VERSION 5.7 ;
  NOWIREEXTENSIONATPIN ON ;
  DIVIDERCHAR "/" ;
  BUSBITCHARS "[]" ;
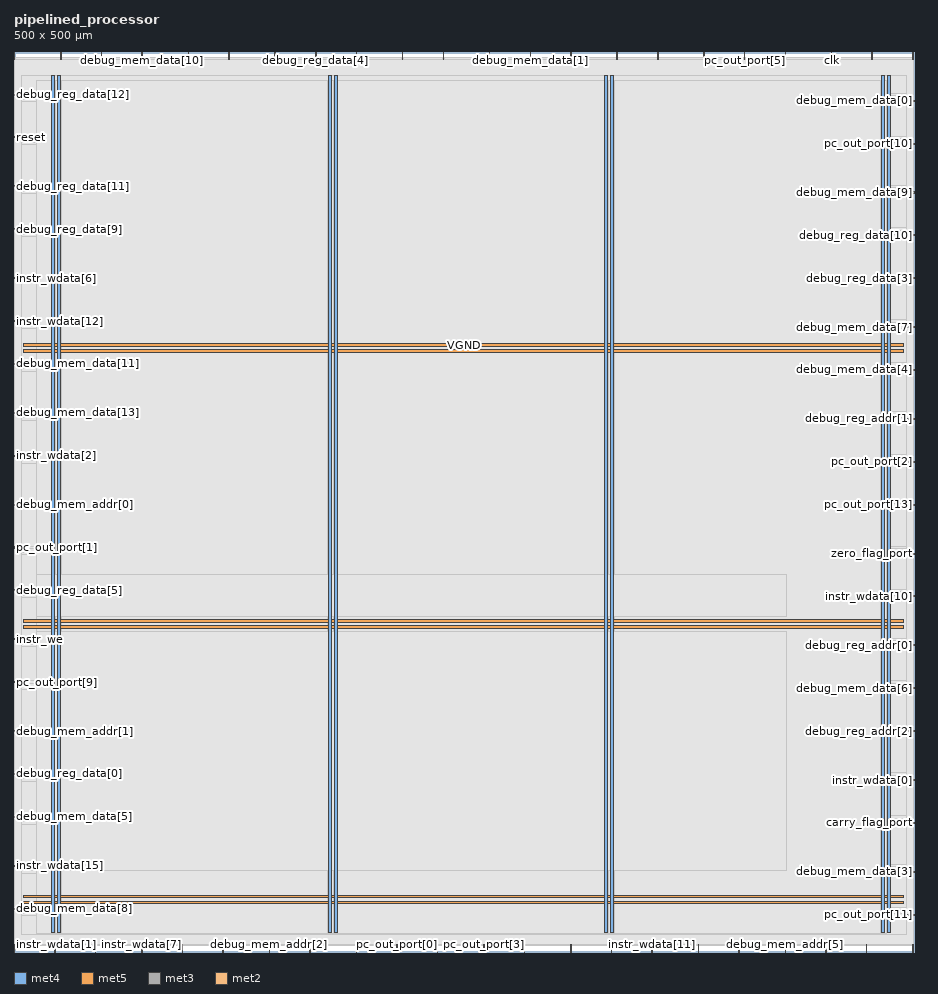
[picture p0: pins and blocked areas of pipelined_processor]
MACRO pipelined_processor
  CLASS BLOCK ;
  FOREIGN pipelined_processor ;
  ORIGIN 0.000 0.000 ;
  SIZE 500.000 BY 500.000 ;
  PIN VGND
    DIRECTION INOUT ;
    USE GROUND ;
    PORT
      LAYER met4 ;
        RECT 24.340 10.640 25.940 487.120 ;
    END
    PORT
      LAYER met4 ;
        RECT 177.940 10.640 179.540 487.120 ;
    END
    PORT
      LAYER met4 ;
        RECT 331.540 10.640 333.140 487.120 ;
    END
    PORT
      LAYER met4 ;
        RECT 485.140 10.640 486.740 487.120 ;
    END
    PORT
      LAYER met5 ;
        RECT 5.280 30.030 494.280 31.630 ;
    END
    PORT
      LAYER met5 ;
        RECT 5.280 183.210 494.280 184.810 ;
    END
    PORT
      LAYER met5 ;
        RECT 5.280 336.390 494.280 337.990 ;
    END
  END VGND
  PIN VPWR
    DIRECTION INOUT ;
    USE POWER ;
    PORT
      LAYER met4 ;
        RECT 21.040 10.640 22.640 487.120 ;
    END
    PORT
      LAYER met4 ;
        RECT 174.640 10.640 176.240 487.120 ;
    END
    PORT
      LAYER met4 ;
        RECT 328.240 10.640 329.840 487.120 ;
    END
    PORT
      LAYER met4 ;
        RECT 481.840 10.640 483.440 487.120 ;
    END
    PORT
      LAYER met5 ;
        RECT 5.280 26.730 494.280 28.330 ;
    END
    PORT
      LAYER met5 ;
        RECT 5.280 179.910 494.280 181.510 ;
    END
    PORT
      LAYER met5 ;
        RECT 5.280 333.090 494.280 334.690 ;
    END
  END VPWR
  PIN carry_flag_port
    DIRECTION OUTPUT TRISTATE ;
    USE SIGNAL ;
    ANTENNADIFFAREA 0.445500 ;
    PORT
      LAYER met3 ;
        RECT 496.000 71.440 500.000 72.040 ;
    END
  END carry_flag_port
  PIN clk
    DIRECTION INPUT ;
    USE SIGNAL ;
    ANTENNAGATEAREA 1.286700 ;
    ANTENNADIFFAREA 0.434700 ;
    PORT
      LAYER met2 ;
        RECT 454.110 496.000 454.390 500.000 ;
    END
  END clk
  PIN debug_mem_addr[0]
    DIRECTION INPUT ;
    USE SIGNAL ;
    ANTENNAGATEAREA 0.213000 ;
    PORT
      LAYER met3 ;
        RECT 0.000 248.240 4.000 248.840 ;
    END
  END debug_mem_addr[0]
  PIN debug_mem_addr[1]
    DIRECTION INPUT ;
    USE SIGNAL ;
    ANTENNAGATEAREA 0.213000 ;
    PORT
      LAYER met3 ;
        RECT 0.000 122.440 4.000 123.040 ;
    END
  END debug_mem_addr[1]
  PIN debug_mem_addr[2]
    DIRECTION INPUT ;
    USE SIGNAL ;
    ANTENNAGATEAREA 0.159000 ;
    PORT
      LAYER met2 ;
        RECT 141.770 0.000 142.050 4.000 ;
    END
  END debug_mem_addr[2]
  PIN debug_mem_addr[3]
    DIRECTION INPUT ;
    USE SIGNAL ;
    ANTENNAGATEAREA 0.213000 ;
    PORT
      LAYER met2 ;
        RECT 235.150 0.000 235.430 4.000 ;
    END
  END debug_mem_addr[3]
  PIN debug_mem_addr[4]
    DIRECTION INPUT ;
    USE SIGNAL ;
    ANTENNAGATEAREA 0.247500 ;
    PORT
      LAYER met2 ;
        RECT 402.590 0.000 402.870 4.000 ;
    END
  END debug_mem_addr[4]
  PIN debug_mem_addr[5]
    DIRECTION INPUT ;
    USE SIGNAL ;
    ANTENNAGATEAREA 0.247500 ;
    PORT
      LAYER met2 ;
        RECT 428.350 0.000 428.630 4.000 ;
    END
  END debug_mem_addr[5]
  PIN debug_mem_data[0]
    DIRECTION OUTPUT TRISTATE ;
    USE SIGNAL ;
    ANTENNADIFFAREA 0.445500 ;
    PORT
      LAYER met3 ;
        RECT 496.000 472.640 500.000 473.240 ;
    END
  END debug_mem_data[0]
  PIN debug_mem_data[10]
    DIRECTION OUTPUT TRISTATE ;
    USE SIGNAL ;
    ANTENNADIFFAREA 0.795200 ;
    PORT
      LAYER met2 ;
        RECT 70.930 496.000 71.210 500.000 ;
    END
  END debug_mem_data[10]
  PIN debug_mem_data[11]
    DIRECTION OUTPUT TRISTATE ;
    USE SIGNAL ;
    ANTENNADIFFAREA 0.795200 ;
    PORT
      LAYER met3 ;
        RECT 0.000 326.440 4.000 327.040 ;
    END
  END debug_mem_data[11]
  PIN debug_mem_data[12]
    DIRECTION OUTPUT TRISTATE ;
    USE SIGNAL ;
    ANTENNADIFFAREA 0.795200 ;
    PORT
      LAYER met2 ;
        RECT 264.130 496.000 264.410 500.000 ;
    END
  END debug_mem_data[12]
  PIN debug_mem_data[13]
    DIRECTION OUTPUT TRISTATE ;
    USE SIGNAL ;
    ANTENNADIFFAREA 0.795200 ;
    PORT
      LAYER met3 ;
        RECT 0.000 299.240 4.000 299.840 ;
    END
  END debug_mem_data[13]
  PIN debug_mem_data[14]
    DIRECTION OUTPUT TRISTATE ;
    USE SIGNAL ;
    ANTENNADIFFAREA 0.795200 ;
    PORT
      LAYER met2 ;
        RECT 499.190 0.000 499.470 4.000 ;
    END
  END debug_mem_data[14]
  PIN debug_mem_data[15]
    DIRECTION OUTPUT TRISTATE ;
    USE SIGNAL ;
    ANTENNADIFFAREA 0.795200 ;
    PORT
      LAYER met2 ;
        RECT 473.430 0.000 473.710 4.000 ;
    END
  END debug_mem_data[15]
  PIN debug_mem_data[1]
    DIRECTION OUTPUT TRISTATE ;
    USE SIGNAL ;
    ANTENNADIFFAREA 0.795200 ;
    PORT
      LAYER met2 ;
        RECT 286.670 496.000 286.950 500.000 ;
    END
  END debug_mem_data[1]
  PIN debug_mem_data[2]
    DIRECTION OUTPUT TRISTATE ;
    USE SIGNAL ;
    ANTENNADIFFAREA 0.795200 ;
    PORT
      LAYER met2 ;
        RECT 383.270 496.000 383.550 500.000 ;
    END
  END debug_mem_data[2]
  PIN debug_mem_data[3]
    DIRECTION OUTPUT TRISTATE ;
    USE SIGNAL ;
    ANTENNADIFFAREA 0.445500 ;
    PORT
      LAYER met3 ;
        RECT 496.000 44.240 500.000 44.840 ;
    END
  END debug_mem_data[3]
  PIN debug_mem_data[4]
    DIRECTION OUTPUT TRISTATE ;
    USE SIGNAL ;
    ANTENNADIFFAREA 0.795200 ;
    PORT
      LAYER met3 ;
        RECT 496.000 323.040 500.000 323.640 ;
    END
  END debug_mem_data[4]
  PIN debug_mem_data[5]
    DIRECTION OUTPUT TRISTATE ;
    USE SIGNAL ;
    ANTENNADIFFAREA 0.795200 ;
    PORT
      LAYER met3 ;
        RECT 0.000 74.840 4.000 75.440 ;
    END
  END debug_mem_data[5]
  PIN debug_mem_data[6]
    DIRECTION OUTPUT TRISTATE ;
    USE SIGNAL ;
    ANTENNADIFFAREA 0.795200 ;
    PORT
      LAYER met3 ;
        RECT 496.000 146.240 500.000 146.840 ;
    END
  END debug_mem_data[6]
  PIN debug_mem_data[7]
    DIRECTION OUTPUT TRISTATE ;
    USE SIGNAL ;
    ANTENNADIFFAREA 0.445500 ;
    PORT
      LAYER met3 ;
        RECT 496.000 346.840 500.000 347.440 ;
    END
  END debug_mem_data[7]
  PIN debug_mem_data[8]
    DIRECTION OUTPUT TRISTATE ;
    USE SIGNAL ;
    ANTENNADIFFAREA 0.795200 ;
    PORT
      LAYER met3 ;
        RECT 0.000 23.840 4.000 24.440 ;
    END
  END debug_mem_data[8]
  PIN debug_mem_data[9]
    DIRECTION OUTPUT TRISTATE ;
    USE SIGNAL ;
    ANTENNADIFFAREA 0.445500 ;
    PORT
      LAYER met3 ;
        RECT 496.000 421.640 500.000 422.240 ;
    END
  END debug_mem_data[9]
  PIN debug_reg_addr[0]
    DIRECTION INPUT ;
    USE SIGNAL ;
    ANTENNAGATEAREA 0.247500 ;
    PORT
      LAYER met3 ;
        RECT 496.000 170.040 500.000 170.640 ;
    END
  END debug_reg_addr[0]
  PIN debug_reg_addr[1]
    DIRECTION INPUT ;
    USE SIGNAL ;
    ANTENNAGATEAREA 0.247500 ;
    PORT
      LAYER met3 ;
        RECT 496.000 295.840 500.000 296.440 ;
    END
  END debug_reg_addr[1]
  PIN debug_reg_addr[2]
    DIRECTION INPUT ;
    USE SIGNAL ;
    ANTENNAGATEAREA 0.495000 ;
    PORT
      LAYER met3 ;
        RECT 496.000 122.440 500.000 123.040 ;
    END
  END debug_reg_addr[2]
  PIN debug_reg_data[0]
    DIRECTION OUTPUT TRISTATE ;
    USE SIGNAL ;
    ANTENNADIFFAREA 0.795200 ;
    PORT
      LAYER met3 ;
        RECT 0.000 98.640 4.000 99.240 ;
    END
  END debug_reg_data[0]
  PIN debug_reg_data[10]
    DIRECTION OUTPUT TRISTATE ;
    USE SIGNAL ;
    ANTENNADIFFAREA 0.445500 ;
    PORT
      LAYER met3 ;
        RECT 496.000 397.840 500.000 398.440 ;
    END
  END debug_reg_data[10]
  PIN debug_reg_data[11]
    DIRECTION OUTPUT TRISTATE ;
    USE SIGNAL ;
    ANTENNADIFFAREA 0.795200 ;
    PORT
      LAYER met3 ;
        RECT 0.000 425.040 4.000 425.640 ;
    END
  END debug_reg_data[11]
  PIN debug_reg_data[12]
    DIRECTION OUTPUT TRISTATE ;
    USE SIGNAL ;
    ANTENNADIFFAREA 0.795200 ;
    PORT
      LAYER met3 ;
        RECT 0.000 476.040 4.000 476.640 ;
    END
  END debug_reg_data[12]
  PIN debug_reg_data[13]
    DIRECTION OUTPUT TRISTATE ;
    USE SIGNAL ;
    ANTENNADIFFAREA 0.795200 ;
    PORT
      LAYER met2 ;
        RECT 0.090 496.000 0.370 500.000 ;
    END
  END debug_reg_data[13]
  PIN debug_reg_data[14]
    DIRECTION OUTPUT TRISTATE ;
    USE SIGNAL ;
    ANTENNADIFFAREA 0.795200 ;
    PORT
      LAYER met2 ;
        RECT 45.170 0.000 45.450 4.000 ;
    END
  END debug_reg_data[14]
  PIN debug_reg_data[15]
    DIRECTION OUTPUT TRISTATE ;
    USE SIGNAL ;
    ANTENNADIFFAREA 0.795200 ;
    PORT
      LAYER met2 ;
        RECT 309.210 496.000 309.490 500.000 ;
    END
  END debug_reg_data[15]
  PIN debug_reg_data[1]
    DIRECTION OUTPUT TRISTATE ;
    USE SIGNAL ;
    ANTENNADIFFAREA 0.795200 ;
    PORT
      LAYER met2 ;
        RECT 190.070 0.000 190.350 4.000 ;
    END
  END debug_reg_data[1]
  PIN debug_reg_data[2]
    DIRECTION OUTPUT TRISTATE ;
    USE SIGNAL ;
    ANTENNADIFFAREA 0.795200 ;
    PORT
      LAYER met2 ;
        RECT 309.210 0.000 309.490 4.000 ;
    END
  END debug_reg_data[2]
  PIN debug_reg_data[3]
    DIRECTION OUTPUT TRISTATE ;
    USE SIGNAL ;
    ANTENNADIFFAREA 0.445500 ;
    PORT
      LAYER met3 ;
        RECT 496.000 374.040 500.000 374.640 ;
    END
  END debug_reg_data[3]
  PIN debug_reg_data[4]
    DIRECTION OUTPUT TRISTATE ;
    USE SIGNAL ;
    ANTENNADIFFAREA 0.795200 ;
    PORT
      LAYER met2 ;
        RECT 167.530 496.000 167.810 500.000 ;
    END
  END debug_reg_data[4]
  PIN debug_reg_data[5]
    DIRECTION OUTPUT TRISTATE ;
    USE SIGNAL ;
    ANTENNADIFFAREA 0.795200 ;
    PORT
      LAYER met3 ;
        RECT 0.000 200.640 4.000 201.240 ;
    END
  END debug_reg_data[5]
  PIN debug_reg_data[6]
    DIRECTION OUTPUT TRISTATE ;
    USE SIGNAL ;
    ANTENNADIFFAREA 0.795200 ;
    PORT
      LAYER met2 ;
        RECT 116.010 0.000 116.290 4.000 ;
    END
  END debug_reg_data[6]
  PIN debug_reg_data[7]
    DIRECTION OUTPUT TRISTATE ;
    USE SIGNAL ;
    ANTENNADIFFAREA 0.795200 ;
    PORT
      LAYER met2 ;
        RECT 380.050 0.000 380.330 4.000 ;
    END
  END debug_reg_data[7]
  PIN debug_reg_data[8]
    DIRECTION OUTPUT TRISTATE ;
    USE SIGNAL ;
    ANTENNADIFFAREA 0.795200 ;
    PORT
      LAYER met2 ;
        RECT 357.510 496.000 357.790 500.000 ;
    END
  END debug_reg_data[8]
  PIN debug_reg_data[9]
    DIRECTION OUTPUT TRISTATE ;
    USE SIGNAL ;
    ANTENNADIFFAREA 0.795200 ;
    PORT
      LAYER met3 ;
        RECT 0.000 401.240 4.000 401.840 ;
    END
  END debug_reg_data[9]
  PIN instr_waddr[0]
    DIRECTION INPUT ;
    USE SIGNAL ;
    ANTENNAGATEAREA 0.213000 ;
    PORT
      LAYER met2 ;
        RECT 283.450 0.000 283.730 4.000 ;
    END
  END instr_waddr[0]
  PIN instr_waddr[1]
    DIRECTION INPUT ;
    USE SIGNAL ;
    ANTENNAGATEAREA 0.159000 ;
    PORT
      LAYER met2 ;
        RECT 25.850 496.000 26.130 500.000 ;
    END
  END instr_waddr[1]
  PIN instr_waddr[2]
    DIRECTION INPUT ;
    USE SIGNAL ;
    ANTENNAGATEAREA 0.495000 ;
    PORT
      LAYER met2 ;
        RECT 450.890 0.000 451.170 4.000 ;
    END
  END instr_waddr[2]
  PIN instr_waddr[3]
    DIRECTION INPUT ;
    USE SIGNAL ;
    ANTENNAGATEAREA 0.247500 ;
    PORT
      LAYER met2 ;
        RECT 190.070 496.000 190.350 500.000 ;
    END
  END instr_waddr[3]
  PIN instr_wdata[0]
    DIRECTION INPUT ;
    USE SIGNAL ;
    ANTENNAGATEAREA 0.426000 ;
    PORT
      LAYER met3 ;
        RECT 496.000 95.240 500.000 95.840 ;
    END
  END instr_wdata[0]
  PIN instr_wdata[10]
    DIRECTION INPUT ;
    USE SIGNAL ;
    ANTENNAGATEAREA 0.247500 ;
    PORT
      LAYER met3 ;
        RECT 496.000 197.240 500.000 197.840 ;
    END
  END instr_wdata[10]
  PIN instr_wdata[11]
    DIRECTION INPUT ;
    USE SIGNAL ;
    ANTENNAGATEAREA 0.247500 ;
    PORT
      LAYER met2 ;
        RECT 354.290 0.000 354.570 4.000 ;
    END
  END instr_wdata[11]
  PIN instr_wdata[12]
    DIRECTION INPUT ;
    USE SIGNAL ;
    ANTENNAGATEAREA 0.159000 ;
    PORT
      LAYER met3 ;
        RECT 0.000 350.240 4.000 350.840 ;
    END
  END instr_wdata[12]
  PIN instr_wdata[13]
    DIRECTION INPUT ;
    USE SIGNAL ;
    ANTENNAGATEAREA 0.213000 ;
    PORT
      LAYER met2 ;
        RECT 144.990 496.000 145.270 500.000 ;
    END
  END instr_wdata[13]
  PIN instr_wdata[14]
    DIRECTION INPUT ;
    USE SIGNAL ;
    ANTENNAGATEAREA 0.213000 ;
    PORT
      LAYER met2 ;
        RECT 238.370 496.000 238.650 500.000 ;
    END
  END instr_wdata[14]
  PIN instr_wdata[15]
    DIRECTION INPUT ;
    USE SIGNAL ;
    ANTENNAGATEAREA 0.213000 ;
    PORT
      LAYER met3 ;
        RECT 0.000 47.640 4.000 48.240 ;
    END
  END instr_wdata[15]
  PIN instr_wdata[1]
    DIRECTION INPUT ;
    USE SIGNAL ;
    ANTENNAGATEAREA 0.247500 ;
    PORT
      LAYER met2 ;
        RECT 0.090 0.000 0.370 4.000 ;
    END
  END instr_wdata[1]
  PIN instr_wdata[2]
    DIRECTION INPUT ;
    USE SIGNAL ;
    ANTENNAGATEAREA 0.159000 ;
    PORT
      LAYER met3 ;
        RECT 0.000 275.440 4.000 276.040 ;
    END
  END instr_wdata[2]
  PIN instr_wdata[3]
    DIRECTION INPUT ;
    USE SIGNAL ;
    ANTENNAGATEAREA 0.213000 ;
    PORT
      LAYER met2 ;
        RECT 215.830 496.000 216.110 500.000 ;
    END
  END instr_wdata[3]
  PIN instr_wdata[4]
    DIRECTION INPUT ;
    USE SIGNAL ;
    ANTENNAGATEAREA 0.213000 ;
    PORT
      LAYER met2 ;
        RECT 334.970 496.000 335.250 500.000 ;
    END
  END instr_wdata[4]
  PIN instr_wdata[5]
    DIRECTION INPUT ;
    USE SIGNAL ;
    ANTENNAGATEAREA 0.247500 ;
    PORT
      LAYER met2 ;
        RECT 476.650 496.000 476.930 500.000 ;
    END
  END instr_wdata[5]
  PIN instr_wdata[6]
    DIRECTION INPUT ;
    USE SIGNAL ;
    ANTENNAGATEAREA 0.213000 ;
    PORT
      LAYER met3 ;
        RECT 0.000 374.040 4.000 374.640 ;
    END
  END instr_wdata[6]
  PIN instr_wdata[7]
    DIRECTION INPUT ;
    USE SIGNAL ;
    ANTENNAGATEAREA 0.213000 ;
    PORT
      LAYER met2 ;
        RECT 70.930 0.000 71.210 4.000 ;
    END
  END instr_wdata[7]
  PIN instr_wdata[8]
    DIRECTION INPUT ;
    USE SIGNAL ;
    ANTENNAGATEAREA 0.213000 ;
    PORT
      LAYER met2 ;
        RECT 22.630 0.000 22.910 4.000 ;
    END
  END instr_wdata[8]
  PIN instr_wdata[9]
    DIRECTION INPUT ;
    USE SIGNAL ;
    ANTENNAGATEAREA 0.426000 ;
    PORT
      LAYER met2 ;
        RECT 499.190 496.000 499.470 500.000 ;
    END
  END instr_wdata[9]
  PIN instr_we
    DIRECTION INPUT ;
    USE SIGNAL ;
    ANTENNAGATEAREA 0.213000 ;
    PORT
      LAYER met3 ;
        RECT 0.000 173.440 4.000 174.040 ;
    END
  END instr_we
  PIN pc_out_port[0]
    DIRECTION OUTPUT TRISTATE ;
    USE SIGNAL ;
    ANTENNADIFFAREA 0.795200 ;
    PORT
      LAYER met2 ;
        RECT 212.610 0.000 212.890 4.000 ;
    END
  END pc_out_port[0]
  PIN pc_out_port[10]
    DIRECTION OUTPUT TRISTATE ;
    USE SIGNAL ;
    ANTENNADIFFAREA 0.445500 ;
    PORT
      LAYER met3 ;
        RECT 496.000 448.840 500.000 449.440 ;
    END
  END pc_out_port[10]
  PIN pc_out_port[11]
    DIRECTION OUTPUT TRISTATE ;
    USE SIGNAL ;
    ANTENNADIFFAREA 0.445500 ;
    PORT
      LAYER met3 ;
        RECT 496.000 20.440 500.000 21.040 ;
    END
  END pc_out_port[11]
  PIN pc_out_port[12]
    DIRECTION OUTPUT TRISTATE ;
    USE SIGNAL ;
    ANTENNADIFFAREA 0.795200 ;
    PORT
      LAYER met2 ;
        RECT 96.690 496.000 96.970 500.000 ;
    END
  END pc_out_port[12]
  PIN pc_out_port[13]
    DIRECTION OUTPUT TRISTATE ;
    USE SIGNAL ;
    ANTENNADIFFAREA 0.445500 ;
    PORT
      LAYER met3 ;
        RECT 496.000 248.240 500.000 248.840 ;
    END
  END pc_out_port[13]
  PIN pc_out_port[14]
    DIRECTION OUTPUT TRISTATE ;
    USE SIGNAL ;
    ANTENNADIFFAREA 0.795200 ;
    PORT
      LAYER met2 ;
        RECT 93.470 0.000 93.750 4.000 ;
    END
  END pc_out_port[14]
  PIN pc_out_port[15]
    DIRECTION OUTPUT TRISTATE ;
    USE SIGNAL ;
    ANTENNADIFFAREA 0.795200 ;
    PORT
      LAYER met2 ;
        RECT 164.310 0.000 164.590 4.000 ;
    END
  END pc_out_port[15]
  PIN pc_out_port[1]
    DIRECTION OUTPUT TRISTATE ;
    USE SIGNAL ;
    ANTENNADIFFAREA 0.795200 ;
    PORT
      LAYER met3 ;
        RECT 0.000 224.440 4.000 225.040 ;
    END
  END pc_out_port[1]
  PIN pc_out_port[2]
    DIRECTION OUTPUT TRISTATE ;
    USE SIGNAL ;
    ANTENNADIFFAREA 0.445500 ;
    PORT
      LAYER met3 ;
        RECT 496.000 272.040 500.000 272.640 ;
    END
  END pc_out_port[2]
  PIN pc_out_port[3]
    DIRECTION OUTPUT TRISTATE ;
    USE SIGNAL ;
    ANTENNADIFFAREA 0.795200 ;
    PORT
      LAYER met2 ;
        RECT 260.910 0.000 261.190 4.000 ;
    END
  END pc_out_port[3]
  PIN pc_out_port[4]
    DIRECTION OUTPUT TRISTATE ;
    USE SIGNAL ;
    ANTENNADIFFAREA 0.795200 ;
    PORT
      LAYER met2 ;
        RECT 428.350 496.000 428.630 500.000 ;
    END
  END pc_out_port[4]
  PIN pc_out_port[5]
    DIRECTION OUTPUT TRISTATE ;
    USE SIGNAL ;
    ANTENNADIFFAREA 0.795200 ;
    PORT
      LAYER met2 ;
        RECT 405.810 496.000 406.090 500.000 ;
    END
  END pc_out_port[5]
  PIN pc_out_port[6]
    DIRECTION OUTPUT TRISTATE ;
    USE SIGNAL ;
    ANTENNADIFFAREA 0.795200 ;
    PORT
      LAYER met2 ;
        RECT 48.390 496.000 48.670 500.000 ;
    END
  END pc_out_port[6]
  PIN pc_out_port[7]
    DIRECTION OUTPUT TRISTATE ;
    USE SIGNAL ;
    ANTENNADIFFAREA 0.795200 ;
    PORT
      LAYER met2 ;
        RECT 119.230 496.000 119.510 500.000 ;
    END
  END pc_out_port[7]
  PIN pc_out_port[8]
    DIRECTION OUTPUT TRISTATE ;
    USE SIGNAL ;
    ANTENNADIFFAREA 0.795200 ;
    PORT
      LAYER met2 ;
        RECT 331.750 0.000 332.030 4.000 ;
    END
  END pc_out_port[8]
  PIN pc_out_port[9]
    DIRECTION OUTPUT TRISTATE ;
    USE SIGNAL ;
    ANTENNADIFFAREA 0.795200 ;
    PORT
      LAYER met3 ;
        RECT 0.000 149.640 4.000 150.240 ;
    END
  END pc_out_port[9]
  PIN reset
    DIRECTION INPUT ;
    USE SIGNAL ;
    ANTENNAGATEAREA 0.213000 ;
    PORT
      LAYER met3 ;
        RECT 0.000 452.240 4.000 452.840 ;
    END
  END reset
  PIN zero_flag_port
    DIRECTION OUTPUT TRISTATE ;
    USE SIGNAL ;
    ANTENNADIFFAREA 0.795200 ;
    PORT
      LAYER met3 ;
        RECT 496.000 221.040 500.000 221.640 ;
    END
  END zero_flag_port
  OBS
      LAYER li1 ;
        RECT 5.520 10.795 494.040 486.965 ;
      LAYER met1 ;
        RECT 0.070 9.560 499.490 487.520 ;
      LAYER met2 ;
        RECT 0.650 495.720 25.570 496.810 ;
        RECT 26.410 495.720 48.110 496.810 ;
        RECT 48.950 495.720 70.650 496.810 ;
        RECT 71.490 495.720 96.410 496.810 ;
        RECT 97.250 495.720 118.950 496.810 ;
        RECT 119.790 495.720 144.710 496.810 ;
        RECT 145.550 495.720 167.250 496.810 ;
        RECT 168.090 495.720 189.790 496.810 ;
        RECT 190.630 495.720 215.550 496.810 ;
        RECT 216.390 495.720 238.090 496.810 ;
        RECT 238.930 495.720 263.850 496.810 ;
        RECT 264.690 495.720 286.390 496.810 ;
        RECT 287.230 495.720 308.930 496.810 ;
        RECT 309.770 495.720 334.690 496.810 ;
        RECT 335.530 495.720 357.230 496.810 ;
        RECT 358.070 495.720 382.990 496.810 ;
        RECT 383.830 495.720 405.530 496.810 ;
        RECT 406.370 495.720 428.070 496.810 ;
        RECT 428.910 495.720 453.830 496.810 ;
        RECT 454.670 495.720 476.370 496.810 ;
        RECT 477.210 495.720 498.910 496.810 ;
        RECT 0.100 4.280 499.460 495.720 ;
        RECT 0.650 3.670 22.350 4.280 ;
        RECT 23.190 3.670 44.890 4.280 ;
        RECT 45.730 3.670 70.650 4.280 ;
        RECT 71.490 3.670 93.190 4.280 ;
        RECT 94.030 3.670 115.730 4.280 ;
        RECT 116.570 3.670 141.490 4.280 ;
        RECT 142.330 3.670 164.030 4.280 ;
        RECT 164.870 3.670 189.790 4.280 ;
        RECT 190.630 3.670 212.330 4.280 ;
        RECT 213.170 3.670 234.870 4.280 ;
        RECT 235.710 3.670 260.630 4.280 ;
        RECT 261.470 3.670 283.170 4.280 ;
        RECT 284.010 3.670 308.930 4.280 ;
        RECT 309.770 3.670 331.470 4.280 ;
        RECT 332.310 3.670 354.010 4.280 ;
        RECT 354.850 3.670 379.770 4.280 ;
        RECT 380.610 3.670 402.310 4.280 ;
        RECT 403.150 3.670 428.070 4.280 ;
        RECT 428.910 3.670 450.610 4.280 ;
        RECT 451.450 3.670 473.150 4.280 ;
        RECT 473.990 3.670 498.910 4.280 ;
      LAYER met3 ;
        RECT 3.990 477.040 496.000 487.045 ;
        RECT 4.400 475.640 496.000 477.040 ;
        RECT 3.990 473.640 496.000 475.640 ;
        RECT 3.990 472.240 495.600 473.640 ;
        RECT 3.990 453.240 496.000 472.240 ;
        RECT 4.400 451.840 496.000 453.240 ;
        RECT 3.990 449.840 496.000 451.840 ;
        RECT 3.990 448.440 495.600 449.840 ;
        RECT 3.990 426.040 496.000 448.440 ;
        RECT 4.400 424.640 496.000 426.040 ;
        RECT 3.990 422.640 496.000 424.640 ;
        RECT 3.990 421.240 495.600 422.640 ;
        RECT 3.990 402.240 496.000 421.240 ;
        RECT 4.400 400.840 496.000 402.240 ;
        RECT 3.990 398.840 496.000 400.840 ;
        RECT 3.990 397.440 495.600 398.840 ;
        RECT 3.990 375.040 496.000 397.440 ;
        RECT 4.400 373.640 495.600 375.040 ;
        RECT 3.990 351.240 496.000 373.640 ;
        RECT 4.400 349.840 496.000 351.240 ;
        RECT 3.990 347.840 496.000 349.840 ;
        RECT 3.990 346.440 495.600 347.840 ;
        RECT 3.990 327.440 496.000 346.440 ;
        RECT 4.400 326.040 496.000 327.440 ;
        RECT 3.990 324.040 496.000 326.040 ;
        RECT 3.990 322.640 495.600 324.040 ;
        RECT 3.990 300.240 496.000 322.640 ;
        RECT 4.400 298.840 496.000 300.240 ;
        RECT 3.990 296.840 496.000 298.840 ;
        RECT 3.990 295.440 495.600 296.840 ;
        RECT 3.990 276.440 496.000 295.440 ;
        RECT 4.400 275.040 496.000 276.440 ;
        RECT 3.990 273.040 496.000 275.040 ;
        RECT 3.990 271.640 495.600 273.040 ;
        RECT 3.990 249.240 496.000 271.640 ;
        RECT 4.400 247.840 495.600 249.240 ;
        RECT 3.990 225.440 496.000 247.840 ;
        RECT 4.400 224.040 496.000 225.440 ;
        RECT 3.990 222.040 496.000 224.040 ;
        RECT 3.990 220.640 495.600 222.040 ;
        RECT 3.990 201.640 496.000 220.640 ;
        RECT 4.400 200.240 496.000 201.640 ;
        RECT 3.990 198.240 496.000 200.240 ;
        RECT 3.990 196.840 495.600 198.240 ;
        RECT 3.990 174.440 496.000 196.840 ;
        RECT 4.400 173.040 496.000 174.440 ;
        RECT 3.990 171.040 496.000 173.040 ;
        RECT 3.990 169.640 495.600 171.040 ;
        RECT 3.990 150.640 496.000 169.640 ;
        RECT 4.400 149.240 496.000 150.640 ;
        RECT 3.990 147.240 496.000 149.240 ;
        RECT 3.990 145.840 495.600 147.240 ;
        RECT 3.990 123.440 496.000 145.840 ;
        RECT 4.400 122.040 495.600 123.440 ;
        RECT 3.990 99.640 496.000 122.040 ;
        RECT 4.400 98.240 496.000 99.640 ;
        RECT 3.990 96.240 496.000 98.240 ;
        RECT 3.990 94.840 495.600 96.240 ;
        RECT 3.990 75.840 496.000 94.840 ;
        RECT 4.400 74.440 496.000 75.840 ;
        RECT 3.990 72.440 496.000 74.440 ;
        RECT 3.990 71.040 495.600 72.440 ;
        RECT 3.990 48.640 496.000 71.040 ;
        RECT 4.400 47.240 496.000 48.640 ;
        RECT 3.990 45.240 496.000 47.240 ;
        RECT 3.990 43.840 495.600 45.240 ;
        RECT 3.990 24.840 496.000 43.840 ;
        RECT 4.400 23.440 496.000 24.840 ;
        RECT 3.990 21.440 496.000 23.440 ;
        RECT 3.990 20.040 495.600 21.440 ;
        RECT 3.990 9.695 496.000 20.040 ;
      LAYER met4 ;
        RECT 12.750 10.240 20.640 483.985 ;
        RECT 23.040 10.240 23.940 483.985 ;
        RECT 26.340 10.240 174.240 483.985 ;
        RECT 176.640 10.240 177.540 483.985 ;
        RECT 179.940 10.240 327.840 483.985 ;
        RECT 330.240 10.240 331.140 483.985 ;
        RECT 333.540 10.240 481.440 483.985 ;
        RECT 483.840 10.240 484.545 483.985 ;
        RECT 12.750 9.695 484.545 10.240 ;
      LAYER met5 ;
        RECT 12.540 186.410 429.060 209.900 ;
        RECT 12.540 45.100 429.060 178.310 ;
  END
END pipelined_processor
END LIBRARY

